VERSION 5.7 ;
  NOWIREEXTENSIONATPIN ON ;
  DIVIDERCHAR "/" ;
  BUSBITCHARS "[]" ;
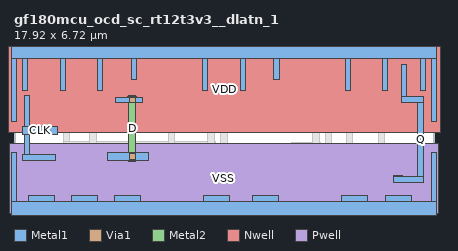
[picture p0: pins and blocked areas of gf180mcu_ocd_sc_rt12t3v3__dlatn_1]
MACRO gf180mcu_ocd_sc_rt12t3v3__dlatn_1
  CLASS CORE ;
  FOREIGN gf180mcu_ocd_sc_rt12t3v3__dlatn_1 ;
  ORIGIN 0.000 0.000 ;
  SIZE 17.920 BY 6.720 ;
  SYMMETRY X Y ;
  SITE unithd ;
  PIN D
    DIRECTION INPUT ;
    USE SIGNAL ;
    ANTENNAGATEAREA 1.672300 ;
    PORT
      LAYER Metal1 ;
        RECT 4.850 4.770 5.230 4.790 ;
        RECT 4.340 4.540 5.480 4.770 ;
        RECT 4.850 4.530 5.230 4.540 ;
        RECT 3.970 2.075 5.730 2.405 ;
      LAYER Via1 ;
        RECT 4.910 4.530 5.170 4.790 ;
        RECT 4.910 2.105 5.170 2.365 ;
      LAYER Metal2 ;
        RECT 4.900 2.045 5.180 4.855 ;
    END
  END D
  PIN CLK
    DIRECTION INPUT ;
    USE SIGNAL ;
    ANTENNAGATEAREA 1.672300 ;
    PORT
      LAYER Metal1 ;
        RECT 0.445 3.525 0.675 4.825 ;
        RECT 0.370 3.195 1.870 3.525 ;
        RECT 0.445 2.320 0.675 3.195 ;
        RECT 0.345 2.090 1.770 2.320 ;
    END
  END CLK
  PIN Q
    DIRECTION OUTPUT ;
    USE SIGNAL ;
    ANTENNADIFFAREA 0.976900 ;
    PORT
      LAYER Metal1 ;
        RECT 16.525 4.820 16.755 6.180 ;
        RECT 16.525 4.560 17.490 4.820 ;
        RECT 16.210 1.380 16.590 1.425 ;
        RECT 17.230 1.380 17.490 4.560 ;
        RECT 16.210 1.120 17.490 1.380 ;
    END
  END Q
  PIN VDD
    DIRECTION INOUT ;
    USE POWER ;
    SHAPE ABUTMENT ;
    PORT
      LAYER Nwell ;
        RECT -0.450 3.245 18.530 7.330 ;
      LAYER Metal1 ;
        RECT -0.115 6.420 18.035 7.020 ;
        RECT -0.115 3.745 0.115 6.420 ;
        RECT 0.365 5.060 0.595 6.420 ;
        RECT 1.965 5.060 2.195 6.420 ;
        RECT 3.565 5.065 3.795 6.420 ;
        RECT 5.005 5.520 5.235 6.420 ;
        RECT 8.045 5.060 8.275 6.420 ;
        RECT 9.645 5.045 9.875 6.420 ;
        RECT 11.085 5.520 11.315 6.420 ;
        RECT 14.125 5.060 14.355 6.420 ;
        RECT 15.725 5.060 15.955 6.420 ;
        RECT 17.325 5.065 17.555 6.420 ;
        RECT 17.805 3.750 18.035 6.420 ;
    END
  END VDD
  PIN VSS
    DIRECTION INOUT ;
    USE GROUND ;
    SHAPE ABUTMENT ;
    PORT
      LAYER Pwell ;
        RECT -0.180 -0.180 18.100 2.815 ;
      LAYER Metal1 ;
        RECT -0.115 0.300 0.115 2.410 ;
        RECT 0.600 0.300 1.710 0.585 ;
        RECT 2.450 0.300 3.560 0.585 ;
        RECT 4.300 0.300 5.410 0.585 ;
        RECT 8.095 0.300 9.205 0.585 ;
        RECT 10.190 0.300 11.300 0.585 ;
        RECT 13.980 0.300 15.090 0.585 ;
        RECT 15.830 0.300 16.940 0.585 ;
        RECT 17.805 0.300 18.035 2.410 ;
        RECT -0.115 -0.300 18.035 0.300 ;
    END
  END VSS
  OBS
      LAYER Metal1 ;
        RECT 1.165 4.820 1.395 6.180 ;
        RECT 2.765 4.820 2.995 6.180 ;
        RECT 4.205 5.290 4.435 6.190 ;
        RECT 5.805 5.960 7.635 6.190 ;
        RECT 8.845 6.070 9.075 6.160 ;
        RECT 5.805 5.290 6.035 5.960 ;
        RECT 4.205 5.060 6.035 5.290 ;
        RECT 6.590 4.975 6.850 5.730 ;
        RECT 7.405 5.055 7.635 5.960 ;
        RECT 8.830 5.065 9.090 6.070 ;
        RECT 10.285 5.290 10.515 6.190 ;
        RECT 11.885 5.960 13.715 6.190 ;
        RECT 11.885 5.290 12.115 5.960 ;
        RECT 1.165 4.560 2.535 4.820 ;
        RECT 2.765 4.560 3.550 4.820 ;
        RECT 6.605 4.770 6.850 4.975 ;
        RECT 2.110 4.540 2.535 4.560 ;
        RECT 2.110 2.875 2.370 4.540 ;
        RECT 3.220 4.300 3.500 4.560 ;
        RECT 5.985 4.540 6.375 4.770 ;
        RECT 6.605 4.540 7.945 4.770 ;
        RECT 8.195 4.565 8.585 4.830 ;
        RECT 8.835 4.770 9.065 5.065 ;
        RECT 10.285 5.060 12.115 5.290 ;
        RECT 12.685 4.980 13.010 5.725 ;
        RECT 13.485 5.055 13.715 5.960 ;
        RECT 14.925 4.820 15.155 6.180 ;
        RECT 6.090 4.300 6.320 4.540 ;
        RECT 3.220 4.070 7.935 4.300 ;
        RECT 7.705 3.805 7.935 4.070 ;
        RECT 8.270 4.290 8.500 4.565 ;
        RECT 8.835 4.540 10.905 4.770 ;
        RECT 14.925 4.560 15.810 4.820 ;
        RECT 15.550 4.290 15.810 4.560 ;
        RECT 8.270 4.060 12.610 4.290 ;
        RECT 14.200 4.060 15.320 4.290 ;
        RECT 15.550 4.060 16.910 4.290 ;
        RECT 7.705 3.575 13.530 3.805 ;
        RECT 2.110 2.645 8.585 2.875 ;
        RECT 12.690 2.830 13.070 2.845 ;
        RECT 2.110 2.320 2.370 2.645 ;
        RECT 7.105 2.325 7.350 2.645 ;
        RECT 8.200 2.610 8.585 2.645 ;
        RECT 11.850 2.600 13.070 2.830 ;
        RECT 11.850 2.345 12.080 2.600 ;
        RECT 12.690 2.585 13.070 2.600 ;
        RECT 13.300 2.350 13.530 3.575 ;
        RECT 2.110 2.090 3.495 2.320 ;
        RECT 6.240 2.095 7.350 2.325 ;
        RECT 9.205 2.320 12.080 2.345 ;
        RECT 7.590 2.115 12.080 2.320 ;
        RECT 12.345 2.120 13.530 2.350 ;
        RECT 14.205 2.320 14.435 4.060 ;
        RECT 15.550 2.320 15.810 4.060 ;
        RECT 7.590 2.090 9.550 2.115 ;
        RECT 14.145 2.090 15.290 2.320 ;
        RECT 2.110 1.425 2.370 2.090 ;
        RECT 3.170 1.425 3.550 1.440 ;
        RECT 5.850 1.425 6.080 1.815 ;
        RECT 0.980 1.195 2.370 1.425 ;
        RECT 2.830 1.195 3.550 1.425 ;
        RECT 4.680 1.195 6.080 1.425 ;
        RECT 3.170 1.180 3.550 1.195 ;
        RECT 5.850 0.770 6.080 1.195 ;
        RECT 6.590 1.440 6.850 1.840 ;
        RECT 7.590 1.440 7.850 2.090 ;
        RECT 14.145 1.885 14.395 2.090 ;
        RECT 6.590 1.180 7.850 1.440 ;
        RECT 8.765 1.425 9.150 1.830 ;
        RECT 9.780 1.655 14.395 1.885 ;
        RECT 15.550 2.075 16.970 2.320 ;
        RECT 9.780 1.425 10.010 1.655 ;
        RECT 15.550 1.430 15.810 2.075 ;
        RECT 14.680 1.425 15.810 1.430 ;
        RECT 8.475 1.195 10.010 1.425 ;
        RECT 10.570 1.195 11.960 1.425 ;
        RECT 6.590 0.720 6.850 1.180 ;
        RECT 8.765 0.815 9.150 1.195 ;
        RECT 9.780 0.980 10.010 1.195 ;
        RECT 11.730 0.740 11.960 1.195 ;
        RECT 12.525 1.165 13.010 1.395 ;
        RECT 14.360 1.195 15.810 1.425 ;
        RECT 12.750 0.755 13.010 1.165 ;
      LAYER Via1 ;
        RECT 6.590 5.035 6.850 5.645 ;
        RECT 8.830 5.125 9.090 6.005 ;
        RECT 3.230 4.560 3.490 4.820 ;
        RECT 8.265 4.565 8.525 4.830 ;
        RECT 12.750 5.040 13.010 5.665 ;
        RECT 8.265 2.610 8.525 2.875 ;
        RECT 12.750 2.585 13.010 2.845 ;
        RECT 3.230 1.180 3.490 1.440 ;
        RECT 6.590 0.785 6.850 1.775 ;
        RECT 8.830 0.815 9.090 1.830 ;
        RECT 12.750 0.815 13.010 1.335 ;
      LAYER Metal2 ;
        RECT 3.220 1.120 3.500 4.880 ;
        RECT 6.580 0.720 6.860 5.705 ;
        RECT 8.255 2.545 8.535 4.890 ;
        RECT 8.820 0.745 9.100 6.075 ;
        RECT 12.740 0.755 13.020 5.770 ;
  END
END gf180mcu_ocd_sc_rt12t3v3__dlatn_1
END LIBRARY

